One B-rep face of a CAD part: STEP entity #204.
In plain terms, the planar face has unit normal (-1, 0, 0).
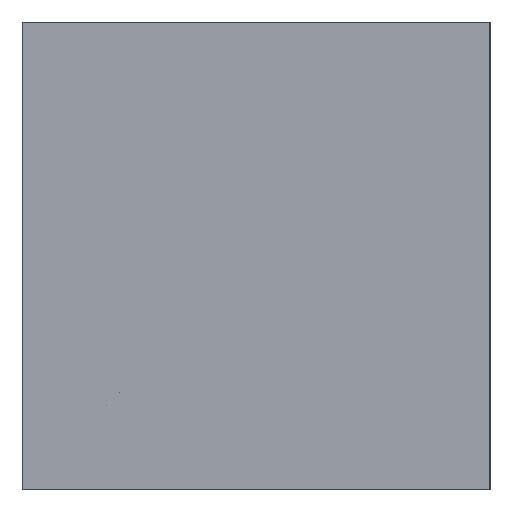
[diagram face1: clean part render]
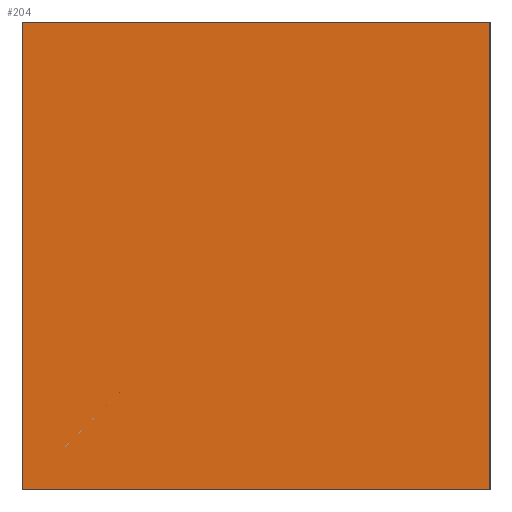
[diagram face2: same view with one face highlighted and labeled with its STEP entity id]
Its self-contained STEP definition (entity closure, numbers rounded to 3 decimals):
#57=CARTESIAN_POINT('Line Origine',(-62.5,30.,0.)) ;
#61=CARTESIAN_POINT('Vertex',(-62.5,30.,-15.)) ;
#63=CARTESIAN_POINT('Vertex',(-62.5,30.,15.)) ;
#174=CARTESIAN_POINT('Axis2P3D Location',(-62.5,0.,-0.)) ;
#179=CARTESIAN_POINT('Line Origine',(-62.5,15.,-15.)) ;
#183=CARTESIAN_POINT('Vertex',(-62.5,0.,-15.)) ;
#186=CARTESIAN_POINT('Line Origine',(-62.5,0.,0.)) ;
#190=CARTESIAN_POINT('Vertex',(-62.5,0.,15.)) ;
#193=CARTESIAN_POINT('Line Origine',(-62.5,15.,15.)) ;
#58=DIRECTION('Vector Direction',(0.,0.,1.)) ;
#175=DIRECTION('Axis2P3D Direction',(1.,0.,-0.)) ;
#176=DIRECTION('Axis2P3D XDirection',(-0.,0.,-1.)) ;
#180=DIRECTION('Vector Direction',(0.,1.,0.)) ;
#187=DIRECTION('Vector Direction',(0.,0.,-1.)) ;
#194=DIRECTION('Vector Direction',(0.,-1.,0.)) ;
#177=AXIS2_PLACEMENT_3D('Plane Axis2P3D',#174,#175,#176) ;
#199=ORIENTED_EDGE('',*,*,#65,.F.) ;
#200=ORIENTED_EDGE('',*,*,#185,.F.) ;
#201=ORIENTED_EDGE('',*,*,#192,.F.) ;
#202=ORIENTED_EDGE('',*,*,#197,.F.) ;
#59=VECTOR('Line Direction',#58,1.) ;
#181=VECTOR('Line Direction',#180,1.) ;
#188=VECTOR('Line Direction',#187,1.) ;
#195=VECTOR('Line Direction',#194,1.) ;
#204=ADVANCED_FACE('760-2534090',(#203),#178,.F.) ;
#65=EDGE_CURVE('',#62,#64,#60,.T.) ;
#185=EDGE_CURVE('',#184,#62,#182,.T.) ;
#192=EDGE_CURVE('',#191,#184,#189,.T.) ;
#197=EDGE_CURVE('',#64,#191,#196,.T.) ;
#198=EDGE_LOOP('',(#199,#200,#201,#202)) ;
#203=FACE_OUTER_BOUND('',#198,.T.) ;
#60=LINE('Line',#57,#59) ;
#182=LINE('Line',#179,#181) ;
#189=LINE('Line',#186,#188) ;
#196=LINE('Line',#193,#195) ;
#178=PLANE('Plane',#177) ;
#62=VERTEX_POINT('',#61) ;
#64=VERTEX_POINT('',#63) ;
#184=VERTEX_POINT('',#183) ;
#191=VERTEX_POINT('',#190) ;
